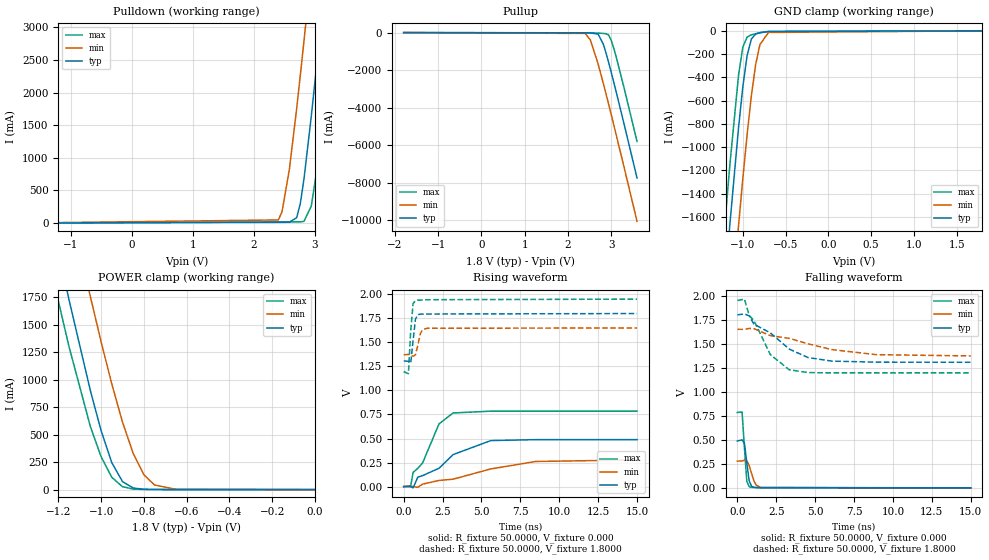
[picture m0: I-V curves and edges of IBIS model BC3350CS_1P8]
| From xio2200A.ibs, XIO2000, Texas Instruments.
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|   Model BC3350CS_1P8
[Model]   BC3350CS_1P8
Model_type   I/O
Polarity   Non-Inverting
Enable   Active-Low
Vinl =   0.54V
Vinh =   1.26V
Vmeas =   0.9V
Cref =   15.0pF
Rref =   100M
Vref =   0.00V
|   typ   min   max
C_comp   1.63pF   1.63pF   1.64pF
[Model Spec]
|   typ   min   max
Vinh   1.260V   1.155V   1.365V
Vinl   0.540V   0.495V   0.585V
Vmeas   0.900V   0.825V   0.975V
[Temperature Range]   25.0   125.0   -40.0
[Voltage Range]   1.80V   1.65V   1.95V
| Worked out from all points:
|   slope of the pulldown table from 0 to 0.27 V, typ, clamps not added: 51.9 ohm
|   slope of the pullup table from 0 to 0.27 V, typ, clamps not added: 72 ohm
|   GND clamp passes 1 mA (typ) near -0.59 V on its own axis
|   POWER clamp passes 1 mA (typ) near -0.75 V on its own axis
|   rising waveform, R_fixture 50.0000, V_fixture 0.000: 20-80 % time 2.74ns typ, 5.16ns min, 1.54ns max; typ from 0 V to 0.488 V
|   rising waveform, R_fixture 50.0000, V_fixture 1.8000: 20-80 % time 199ps typ, 241ps min, 188ps max; typ from 1.31 V to 1.8 V
|   falling waveform, R_fixture 50.0000, V_fixture 0.000: 20-80 % time 230ps typ, 348ps min, 199ps max; typ from 0.488 V to 0 V
|   falling waveform, R_fixture 50.0000, V_fixture 1.8000: 20-80 % time 2.65ns typ, 4.66ns min, 1.55ns max; typ from 1.8 V to 1.31 V
| (Vdd votage range)   1.50V   1.35V   1.65V
| (Process strength)   nominal   weak   strong
[Pulldown]
| voltage   I(typ)   I(min)   I(max)
-1.8V     -654.2uA   -468.5uA   -753.5uA
2.4V      10.51mA    46.93mA    15.78mA
2.46V     10.7mA     169.4mA    15.83mA
2.58V     12.15mA    818.2mA    16.11mA
2.7V      81.06mA    1.755A     16.82mA
2.76V     300.4mA    2.267A     17.73mA
2.82V     678.1mA    2.795A     25.01mA
2.94V     1.642A     3.882A     262.8mA
3.06V     2.709A     4.995A     991.1mA
3.12V     3.26A      5.558A     1.466A
3.3V      4.95A      7.266A     3.059A
3.6V      7.83A      10.15A     5.897A
[Pullup]
| voltage   I(typ)   I(min)   I(max)
-1.8V     538uA      376.5uA    737.9uA
2.4V      -11.82mA   -45.61mA   -17.67mA
2.52V     -17.7mA    -390.5mA   -18.1mA
2.7V      -80.03mA   -1.677A    -28.29mA
2.82V     -618.6mA   -2.71A     -45.98mA
2.88V     -1.07A     -3.247A    -60.47mA
2.94V     -1.568A    -3.794A    -125.5mA
3V        -2.092A    -4.347A    -388.2mA
3.06V     -2.632A    -4.905A    -816.6mA
3.12V     -3.182A    -5.468A    -1.314A
3.3V      -4.872A    -7.174A    -2.945A
3.6V      -7.751A    -10.06A    -5.806A
[GND_clamp]
| voltage   I(typ)   I(min)   I(max)
-1.8V     -7.751A    -8.611A    -7.26A
-1.25V    -2.54A     -3.428A    -2.021A
-1.2V     -2.091A    -2.977A    -1.573A
-1.15V    -1.653A    -2.533A    -1.141A
-1.05V    -833.6mA   -1.675A    -381.3mA
-1V       -481.8mA   -1.271A    -140.2mA
-950mV    -212.8mA   -893.9mA   -53.78mA
-900mV    -70.89mA   -558.6mA   -34.35mA
-850mV    -27.49mA   -290.5mA   -24.87mA
-800mV    -15.42mA   -118.3mA   -17.13mA
-700mV    -5.579mA   -14.05mA   -5.6mA
1.8V      108.1pA    25.63nA    93.5pA
[POWER_clamp]
| voltage   I(typ)   I(min)   I(max)
-1.8V     7.829A     8.704A     7.346A
-1.2V     2.167A     3.062A     1.716A
-1.15V    1.727A     2.616A     1.3A
-1.05V    899.2mA    1.754A     572.6mA
-1V       536.3mA    1.345A     298.8mA
-950mV    245.3mA    960.6mA    111.5mA
-900mV    72.81mA    614.2mA    26.23mA
-850mV    14.59mA    328.9mA    4.932mA
-800mV    2.989mA    135.1mA    1.575mA
-750mV    997.4uA    41.7mA     924.5uA
-650mV    310.2uA    2.816mA    338.3uA
0V        108.1pA    1.97nA     104.9pA
[Ramp]
| variable   typ   min   max
dV/dt_r   0.2928/2.7176n   0.1664/5.1109n   0.4706/1.5201n
dV/dt_f   0.2955/2.6271n   0.1664/4.6144n   0.4527/1.5357n
R_load = 50.0000
[Rising Waveform]
R_fixture = 50.0000
V_fixture = 0.000
V_fixture_min = 0.000
V_fixture_max = 0.000
| time   V(typ)   V(min)   V(max)
0s        803pV      24.91nV    435.3pV
454.5ps   -1.401mV   777.2uV    8.095mV
606.1ps   -13.53mV   535.4uV    147mV
909.1ps   98.07mV    -8.632mV   190.1mV
1.212ns   113.5mV    25.39mV    244.5mV
2.273ns   190.5mV    63.7mV     652.3mV
3.182ns   332.9mV    76.68mV    765.8mV
5.606ns   478.6mV    183.8mV    784.4mV
8.485ns   487.9mV    260.8mV    784.4mV
15ns      488.1mV    277.4mV    784.4mV
[Rising Waveform]
R_fixture = 50.0000
V_fixture = 1.8000
V_fixture_min = 1.6500
V_fixture_max = 1.9500
| time   V(typ)   V(min)   V(max)
0s        1.307V     1.372V     1.196V
303ps     1.303V     1.374V     1.174V
454.5ps   1.288V     1.367V     1.627V
606.1ps   1.523V     1.355V     1.903V
757.6ps   1.743V     1.371V     1.936V
909.1ps   1.787V     1.468V     1.94V
1.061ns   1.794V     1.586V     1.94V
1.212ns   1.795V     1.632V     1.942V
1.515ns   1.795V     1.647V     1.944V
15ns      1.8V       1.65V      1.95V
[Falling Waveform]
R_fixture = 50.0000
V_fixture = 0.000
V_fixture_min = 0.000
V_fixture_max = 0.000
| time   V(typ)   V(min)   V(max)
0s        488.1mV    277.6mV    784.4mV
303ps     499.3mV    280.5mV    789.8mV
454.5ps   463.6mV    287.6mV    413.6mV
606.1ps   260.4mV    281mV      70.01mV
757.6ps   74.37mV    231.8mV    12.37mV
909.1ps   16.58mV    151.7mV    5.214mV
1.061ns   5.188mV    75.42mV    3.972mV
1.212ns   3.034mV    27.51mV    3.312mV
1.515ns   2.017mV    3.965mV    1.862mV
15ns      21.31nV    2.775uV    242.2nV
[Falling Waveform]
R_fixture = 50.0000
V_fixture = 1.8000
V_fixture_min = 1.6500
V_fixture_max = 1.9500
| time   V(typ)   V(min)   V(max)
0s        1.8V       1.65V      1.95V
454.5ps   1.81V      1.65V      1.964V
757.6ps   1.79V      1.659V     1.795V
1.061ns   1.704V     1.657V     1.742V
2.121ns   1.613V     1.584V     1.386V
3.333ns   1.444V     1.556V     1.229V
4.546ns   1.356V     1.499V     1.2V
6.061ns   1.319V     1.439V     1.196V
8.939ns   1.308V     1.386V     1.196V
15ns      1.307V     1.373V     1.196V
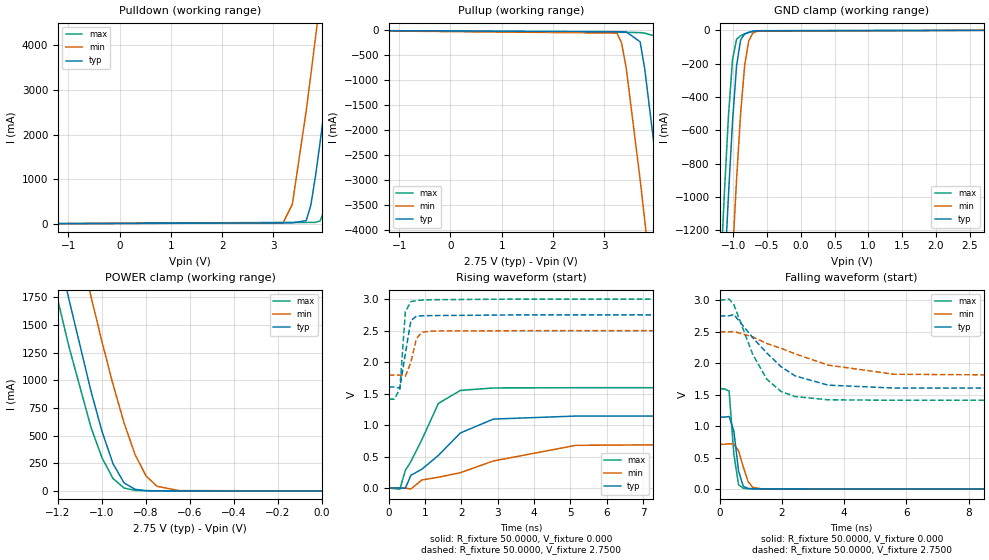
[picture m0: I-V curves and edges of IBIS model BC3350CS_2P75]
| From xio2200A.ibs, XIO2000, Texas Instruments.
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|   Model BC3350CS_2P75
[Model]   BC3350CS_2P75
Model_type   I/O
Polarity   Non-Inverting
Enable   Active-Low
Vinl =   0.8200V
Vinh =   1.9300V
Vmeas =   1.3800V
Cref =   15.0pF
Rref =   100M
Vref =   0.00V
|   typ   min   max
C_comp   1.71pF   1.77pF   1.69pF
[Model Spec]
|   typ   min   max
Vinh   1.93V   1.75V   2.10V
Vinl   0.82V   0.75V   0.90V
Vmeas   1.38V   1.25V   1.50V
[Temperature Range]   25.0   125.0   -40.0
[Voltage Range]   2.75V   2.50V   3.00V
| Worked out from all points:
|   slope of the pulldown table from 0 to 0.412 V, typ, clamps not added: 34.6 ohm
|   slope of the pullup table from 0 to 0.412 V, typ, clamps not added: 48.8 ohm
|   GND clamp passes 1 mA (typ) near -0.59 V on its own axis
|   POWER clamp passes 1 mA (typ) near -0.75 V on its own axis
|   rising waveform, R_fixture 50.0000, V_fixture 0.000: 20-80 % time 1.4ns typ, 2.73ns min, 800ps max; typ from 0 V to 1.14 V
|   rising waveform, R_fixture 50.0000, V_fixture 2.7500: 20-80 % time 195ps typ, 189ps min, 118ps max; typ from 1.6 V to 2.75 V
|   falling waveform, R_fixture 50.0000, V_fixture 0.000: 20-80 % time 187ps typ, 269ps min, 183ps max; typ from 1.14 V to 0 V
|   falling waveform, R_fixture 50.0000, V_fixture 2.7500: 20-80 % time 1.47ns typ, 2.53ns min, 934ps max; typ from 2.75 V to 1.6 V
| (Vdd votage range)   1.50V   1.35V   1.65V
| (Process strength)   nominal   weak   strong
[Pulldown]
| voltage   I(typ)   I(min)   I(max)
-2.75V    -428uA     -334uA     -470uA
3.19V     23.93mA    22.8mA     33.02mA
3.37V     24.22mA    440.4mA    33.12mA
3.64V     74.24mA    2.53A      33.58mA
3.73V     418.4mA    3.335A     34.11mA
3.82V     1.061A     4.159A     35.52mA
3.91V     1.817A     4.995A     66.01mA
4V        2.619A     5.842A     316.8mA
4.18V     4.289A     7.553A     1.552A
4.45V     6.865A     10.15A     3.993A
4.54V     7.733A     11.02A     4.845A
5.44V     16.53A     19.82A     13.61A
[Pullup]
| voltage   I(typ)   I(min)   I(max)
-2.69V    349uA      272uA      421uA
3.25V     -26.63mA   -54.43mA   -39.52mA
3.34V     -27.5mA    -257mA     -39.61mA
3.43V     -30.87mA   -758.6mA   -39.71mA
3.7V      -228.6mA   -2.978A    -45.23mA
3.79V     -765.9mA   -3.794A    -55.21mA
3.97V     -2.272A    -5.468A    -108.9mA
4.06V     -3.091A    -6.318A    -459.5mA
4.15V     -3.929A    -7.174A    -1.147A
4.42V     -6.497A    -9.768A    -3.604A
4.51V     -7.365A    -10.64A    -4.46A
5.5V      -17.05A    -20.32A    -14.13A
[GND_clamp]
| voltage   I(typ)   I(min)   I(max)
-2.75V    -17.05A    -17.86A    -16.59A
-1.19V    -2.002A    -2.887A    -1.485A
-1.13V    -1.481A    -2.357A    -974mA
-1.07V    -988.2mA   -1.843A    -513.5mA
-1.01V    -547.1mA   -1.35A     -175.6mA
-950mV    -212.8mA   -893.9mA   -53.78mA
-890mV    -56.89mA   -498.7mA   -32.19mA
-830mV    -21.15mA   -209mA     -21.63mA
-770mV    -11.63mA   -62.48mA   -13.06mA
-710mV    -6.281mA   -17.15mA   -6.465mA
-650mV    -2.795mA   -5.685mA   -2.37mA
2.71V     161.2pA    121.2nA    140.1pA
[POWER_clamp]
| voltage   I(typ)   I(min)   I(max)
-2.75V    17.12A     17.96A     16.66A
-1.2V     2.167A     3.062A     1.716A
-1.15V    1.727A     2.616A     1.3A
-1.05V    899.2mA    1.754A     572.6mA
-1V       536.3mA    1.345A     298.8mA
-950mV    245.3mA    960.6mA    111.5mA
-900mV    72.81mA    614.2mA    26.23mA
-850mV    14.59mA    328.9mA    4.932mA
-800mV    2.989mA    135.1mA    1.575mA
-750mV    997.4uA    41.7mA     924.5uA
-650mV    310.2uA    2.816mA    338.3uA
0V        166.9pA    2.584nA    161.6pA
[Ramp]
| variable   typ   min   max
dV/dt_r   0.6862/1.3889n   0.4277/2.7000n   0.9559/0.7918n
dV/dt_f   0.6878/1.4530n   0.4241/2.5089n   0.9530/0.9244n
R_load = 50.0000
[Rising Waveform]
R_fixture = 50.0000
V_fixture = 0.000
V_fixture_min = 0.000
V_fixture_max = 0.000
| time   V(typ)   V(min)   V(max)
0s        1.165nV    30.15nV    566.8pV
303ps     245.9uV    982.9uV    -17.68mV
454.5ps   -3.561mV   -1.183mV   282.1mV
606.1ps   202.5mV    -15.34mV   419.4mV
909.1ps   299.3mV    128mV      767.5mV
1.364ns   518.6mV    171.9mV    1.343V
1.97ns    874.7mV    243.5mV    1.55V
2.879ns   1.095V     429.9mV    1.589V
5.152ns   1.143V     678.4mV    1.593V
15ns      1.144V     712.9mV    1.593V
[Rising Waveform]
R_fixture = 50.0000
V_fixture = 2.7500
V_fixture_min = 2.5000
V_fixture_max = 3.0000
| time   V(typ)   V(min)   V(max)
0s        1.604V     1.793V     1.412V
151.5ps   1.604V     1.793V     1.412V
303ps     1.585V     1.793V     1.571V
454.5ps   2.136V     1.776V     2.798V
606.1ps   2.66V      1.995V     2.959V
757.6ps   2.728V     2.37V      2.976V
909.1ps   2.734V     2.473V     2.983V
1.212ns   2.738V     2.493V     2.99V
3.636ns   2.749V     2.498V     3V
15ns      2.75V      2.5V       3V
[Falling Waveform]
R_fixture = 50.0000
V_fixture = 0.000
V_fixture_min = 0.000
V_fixture_max = 0.000
| time   V(typ)   V(min)   V(max)
0s        1.144V     712.9mV    1.593V
151.5ps   1.144V     712.9mV    1.593V
303ps     1.154V     720.5mV    1.558V
454.5ps   922.5mV    716.6mV    558.9mV
606.1ps   289.3mV    608.7mV    71mV
757.6ps   44.97mV    353.9mV    14.61mV
909.1ps   11.72mV    125.2mV    7.665mV
1.061ns   7.02mV     28.39mV    5.42mV
1.364ns   4.248mV    3.668mV    2.958mV
15ns      375.4nV    195.7nV    251.4nV
[Falling Waveform]
R_fixture = 50.0000
V_fixture = 2.7500
V_fixture_min = 2.5000
V_fixture_max = 3.0000
| time   V(typ)   V(min)   V(max)
0s        2.75V      2.5V       3V
303ps     2.753V     2.498V     3.019V
454.5ps   2.775V     2.504V     2.931V
1.061ns   2.407V     2.418V     2.142V
1.515ns   2.162V     2.313V     1.746V
1.97ns    1.946V     2.238V     1.552V
2.424ns   1.799V     2.149V     1.471V
3.485ns   1.652V     1.97V      1.419V
5.606ns   1.606V     1.825V     1.412V
15ns      1.604V     1.793V     1.412V
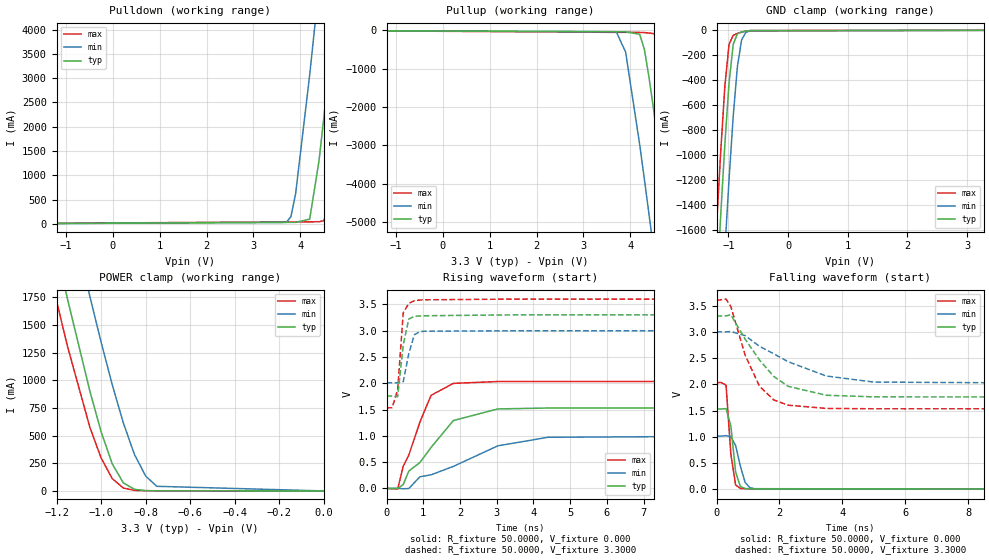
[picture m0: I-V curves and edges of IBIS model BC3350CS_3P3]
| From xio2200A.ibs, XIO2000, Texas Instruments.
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|   Model BC3350CS_3P3
[Model]   BC3350CS_3P3
Model_type   I/O
Enable   Active-Low
Polarity   Non-Inverting
Vinl =   0.99000V
Vinh =   2.31000V
Vmeas =   1.65000V
Cref =  15.00000pF
Rref = 100.00000M
Vref = 0.0000V
|   typ   min   max
C_comp   2.11pf   2.20pf   2.12pf
[Model Spec]
|   typ   min   max
Vinh   2.31V   2.10V   2.52V
Vinl   0.99V   0.90V   1.08V
Vmeas   1.65V   1.50V   1.80V
[Temperature Range]   25.0   125.0   -40.0
[Voltage Range]   3.30V   3.00V   3.60V
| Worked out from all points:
|   slope of the pulldown table from 0 to 0.495 V, typ, clamps not added: 30.8 ohm
|   slope of the pullup table from 0 to 0.495 V, typ, clamps not added: 43 ohm
|   GND clamp passes 1 mA (typ) near -0.59 V on its own axis
|   POWER clamp passes 1 mA (typ) near -0.75 V on its own axis
|   rising waveform, R_fixture 50.0000, V_fixture 0.000: 20-80 % time 1.12ns typ, 2.16ns min, 658ps max; typ from 0 V to 1.53 V
|   rising waveform, R_fixture 50.0000, V_fixture 3.3000: 20-80 % time 182ps typ, 202ps min, 128ps max; typ from 1.76 V to 3.3 V
|   falling waveform, R_fixture 50.0000, V_fixture 0.000: 20-80 % time 172ps typ, 258ps min, 178ps max; typ from 1.53 V to 0 V
|   falling waveform, R_fixture 50.0000, V_fixture 3.3000: 20-80 % time 1.22ns typ, 2.03ns min, 808ps max; typ from 3.3 V to 1.76 V
| (Vdd votage range)   1.50V   1.35V   1.65V
| (Process strength)   nominal   weak   strong
[Pulldown]
| voltage   I(typ)   I(min)   I(max)
-3.3V     -368uA     -295uA     -396uA
3.7V      32.25mA    31.14mA    43.09mA
3.8V      32.33mA    150.2mA    43.16mA
3.9V      32.52mA    621.8mA    43.24mA
4.2V      98.73mA    3.065A     43.69mA
4.4V      1.307A     4.902A     45.29mA
4.5V      2.17A      5.842A     66.67mA
4.6V      3.077A     6.79A      322.6mA
4.8V      4.951A     8.705A     1.723A
4.9V      5.905A     9.668A     2.605A
5.2V      8.8A       12.58A     5.419A
6.6V      22.55A     26.32A     19.14A
[Pullup]
| voltage   I(typ)   I(min)   I(max)
-3.3V     286uA      231uA      330uA
3.7V      -37mA      -36.04mA   -52.76mA
3.9V      -38.31mA   -567.5mA   -52.99mA
4.2V      -102.7mA   -2.979A    -53.99mA
4.3V      -495.7mA   -3.887A    -58.56mA
4.4V      -1.237A    -4.813A    -69.85mA
4.5V      -2.095A    -5.751A    -86.73mA
4.6V      -3A        -6.698A    -177.8mA
4.8V      -4.873A    -8.612A    -1.579A
5.1V      -7.752A    -11.51A    -4.365A
5.2V      -8.722A    -12.48A    -5.324A
6.6V      -22.48A    -26.23A    -19.07A
[GND_clamp]
| voltage   I(typ)   I(min)   I(max)
-3.3V     -22.48A    -23.27A    -22.04A
-1.2V     -2.091A    -2.977A    -1.573A
-1.13V    -1.481A    -2.357A    -974mA
-1.06V    -910.1mA   -1.759A    -445.6mA
-990mV    -419.8mA   -1.193A    -111.9mA
-920mV    -111.8mA   -686.4mA   -39.65mA
-850mV    -27.49mA   -290.5mA   -24.87mA
-780mV    -12.77mA   -77.68mA   -14.36mA
-710mV    -6.281mA   -17.15mA   -6.465mA
-640mV    -2.381mA   -4.808mA   -1.936mA
3.28V     199.9pA    703.3nA    170pA
[POWER_clamp]
| voltage   I(typ)   I(min)   I(max)
-3.3V     22.55A     23.36A     22.1A
-1.25V    2.617A     3.515A     2.152A
-1.2V     2.167A     3.062A     1.716A
-1.15V    1.727A     2.616A     1.3A
-1.05V    899.2mA    1.754A     572.6mA
-1V       536.3mA    1.345A     298.8mA
-950mV    245.3mA    960.6mA    111.5mA
-900mV    72.81mA    614.2mA    26.23mA
-850mV    14.59mA    328.9mA    4.932mA
-800mV    2.989mA    135.1mA    1.575mA
-750mV    997.4uA    41.7mA     924.5uA
0V        203.4pA    3.019nA    194.4pA
[Ramp]
| variable   typ   min   max
dV/dt_r   0.9174/1.1080n   0.6072/2.1416n   1.2196/0.6514n
dV/dt_f   0.9259/1.2121n   0.5953/2.0141n   1.2405/0.7996n
R_load = 50.0000
[Rising Waveform]
R_fixture = 50.0000
V_fixture = 0.000
V_fixture_min = 0.000
V_fixture_max = 0.000
| time   V(typ)   V(min)   V(max)
0s        1.49nV     34.72nV    671.9pV
303ps     -3.357mV   1.385mV    -14.66mV
454.5ps   73.69mV    -7.318mV   421.4mV
606.1ps   329.8mV    -2.808mV   634.3mV
909.1ps   492mV      221.1mV    1.262V
1.212ns   778.4mV    258.3mV    1.769V
1.818ns   1.29V      418mV      1.997V
3.03ns    1.511V     809.2mV    2.032V
4.394ns   1.528V     971.8mV    2.033V
15ns      1.529V     1.012V     2.033V
[Rising Waveform]
R_fixture = 50.0000
V_fixture = 3.3000
V_fixture_min = 3.0000
V_fixture_max = 3.6000
| time   V(typ)   V(min)   V(max)
0s        1.757V     2.008V     1.533V
151.5ps   1.757V     2.008V     1.533V
303ps     1.743V     2.006V     1.872V
454.5ps   2.733V     2.026V     3.338V
606.1ps   3.22V      2.563V     3.518V
757.6ps   3.272V     2.921V     3.57V
909.1ps   3.279V     2.981V     3.581V
1.061ns   3.283V     2.989V     3.586V
3.485ns   3.3V       2.997V     3.6V
15ns      3.3V       3V         3.6V
[Falling Waveform]
R_fixture = 50.0000
V_fixture = 0.000
V_fixture_min = 0.000
V_fixture_max = 0.000
| time   V(typ)   V(min)   V(max)
0s        1.529V     1.012V     2.033V
151.5ps   1.529V     1.012V     2.033V
303ps     1.536V     1.02V      1.984V
454.5ps   1.207V     1.004V     670.5mV
606.1ps   329.7mV    831.6mV    79.49mV
757.6ps   47.92mV    437.4mV    13.47mV
909.1ps   12.78mV    128.5mV    8.217mV
1.061ns   7.667mV    26.97mV    6.068mV
1.212ns   6.065mV    8.864mV    4.526mV
15ns      359.4nV    457.2nV    237.2nV
[Falling Waveform]
R_fixture = 50.0000
V_fixture = 3.3000
V_fixture_min = 3.0000
V_fixture_max = 3.6000
| time   V(typ)   V(min)   V(max)
0s        3.3V       3V         3.6V
303ps     3.305V     2.999V     3.625V
454.5ps   3.325V     3.006V     3.483V
909.1ps   2.86V      2.928V     2.555V
1.364ns   2.463V     2.725V     1.964V
1.818ns   2.15V      2.581V     1.702V
2.273ns   1.961V     2.431V     1.601V
3.485ns   1.791V     2.158V     1.54V
5ns       1.76V      2.042V     1.533V
15ns      1.757V     2.008V     1.533V
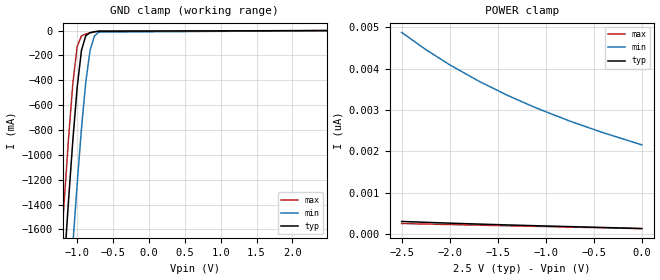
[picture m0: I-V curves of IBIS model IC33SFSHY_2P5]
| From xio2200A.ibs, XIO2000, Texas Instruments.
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|************************ IC33SFSHY @ 2.5V************************
[Model]   IC33SFSHY_2P5
Model_type   Input
Polarity   Non-Inverting
Vinh = 1.75V
Vinl = 0.75V
|   typ   min   max
C_comp   1.563pF   1.592pF   1.553pF
[Model Spec]
|   typ   min   max
Vinh   1.750V   1.575V   1.925V
Vinl   0.750V   0.675V   0.825V
[Temperature Range]   25   125   -40
[Voltage Range]   2.50V   2.25V   2.75V
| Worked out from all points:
|   GND clamp passes 1 mA (typ) near -0.59 V on its own axis
| (Vdd votage range)   1.50V   1.35V   1.65V
[GND_clamp]
| voltage   I(typ)   I(min)   I(max)
-2.5V     -14.56A    -15.37A    -14.1A
-1.24V    -2.42A     -3.298A    -1.907A
-1.18V    -1.885A    -2.759A    -1.375A
-1.12V    -1.369A    -2.232A    -871mA
-1.06V    -884.2mA   -1.722A    -426.9mA
-1V       -460.1mA   -1.237A    -129mA
-940mV    -160.3mA   -792mA     -42.89mA
-880mV    -41.5mA    -417.1mA   -27.16mA
-820mV    -16.93mA   -160.2mA   -18.08mA
-760mV    -9.494mA   -44.89mA   -10.64mA
-700mV    -5.012mA   -12.52mA   -5.062mA
2.48V     130.4pA    2.323nA    114.2pA
[POWER_clamp]
| voltage   I(typ)   I(min)   I(max)
-2.5V     303.5pA    4.879nA    253.7pA
-2.25V    282.2pA    4.465nA    240.9pA
-2V       262.3pA    4.095nA    228.4pA
-1.7V     240.2pA    3.703nA    213.7pA
-1.4V     219.4pA    3.357nA    198.9pA
-1.1V     199.8pA    3.051nA    184.4pA
-750mV    178pA      2.733nA    167.3pA
-400mV    157.1pA    2.45nA     150.6pA
0V        132.2pA    2.158nA    129pA
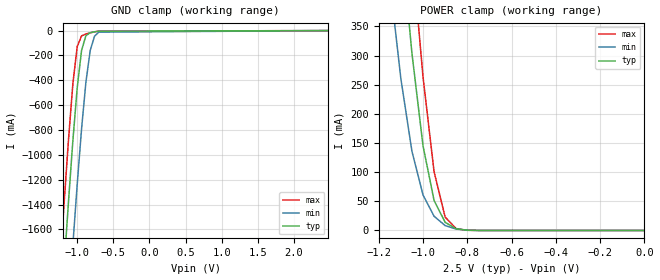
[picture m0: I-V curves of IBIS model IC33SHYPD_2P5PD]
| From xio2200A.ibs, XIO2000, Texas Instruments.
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|   Model IC33SHYPD_2P5PD
[Model]   IC33SHYPD_2P5PD
Model_type   Input
Polarity   Non-Inverting
Vinh =   1.75V
Vinl =   0.75V
|   typ   min   max
C_comp   1.62pF   1.62pF   1.62pF
[Model Spec]
|   typ   min   max
Vinh   1.750V   1.575V   1.925V
Vinl   0.750V   0.675V   0.825V
[Temperature Range]   25.0000   0.1250k   -40.0000
[Voltage Range]   2.5000V   2.2500V   2.7500V
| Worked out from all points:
|   GND clamp passes 1 mA (typ) near -0.59 V on its own axis
|   POWER clamp passes 1 mA (typ) near -0.81 V on its own axis
| (Vdd votage range)   1.50V   1.35V   1.65V
[GND_clamp]
| voltage   I(typ)   I(min)   I(max)
-2.5V     -14.56A    -15.37A    -14.1A
-1.24V    -2.42A     -3.298A    -1.907A
-1.18V    -1.885A    -2.759A    -1.375A
-1.12V    -1.369A    -2.232A    -871mA
-1.06V    -884.3mA   -1.722A    -427mA
-1V       -460.1mA   -1.237A    -129.1mA
-940mV    -160.3mA   -792.1mA   -42.92mA
-880mV    -41.54mA   -417.2mA   -27.16mA
-820mV    -16.95mA   -160.2mA   -18.08mA
-760mV    -9.5mA     -44.93mA   -10.64mA
-700mV    -5.013mA   -12.54mA   -5.062mA
2.48V     143.1pA    2.391nA    127pA
[POWER_clamp]
| voltage   I(typ)   I(min)   I(max)
-2.5V     8.108A     7.368A     8.703A
-1.15V    732.8mA    427.8mA    979.7mA
-1.1V     506.2mA    260.6mA    722.8mA
-1.05V    304.3mA    136mA      480.1mA
-1V       145.5mA    61.04mA    263.8mA
-950mV    51.56mA    24.44mA    101mA
-900mV    14.01mA    8.383mA    22.94mA
-850mV    2.793mA    2.36mA     3.142mA
-800mV    442.5uA    587.5uA    300.2uA
-750mV    66.2uA     140.7uA    26.86uA
0V        145.1pA    2.172nA    143pA
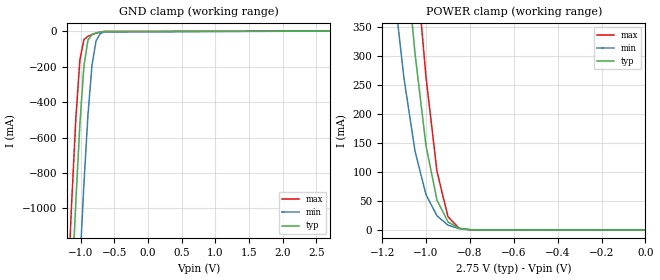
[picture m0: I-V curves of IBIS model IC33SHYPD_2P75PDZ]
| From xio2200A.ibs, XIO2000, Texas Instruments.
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|   Model IC33SHYPD_2P75PDZ
[Model]   IC33SHYPD_2P75PDZ
Model_type   Input
Polarity   Non-Inverting
Vinl =   0.8200V
Vinh =   1.9300V
C_comp   1.6800pF   1.6800pF   1.6800pF
[Model Spec]
|   typ   min   max
Vinh   1.930V   1.750V   2.10V
Vinl   0.820V   0.750V   0.90V
[Temperature Range]   25.0000   0.1250k   -40.0000
[Voltage Range]   2.7500V   2.5000V   3.0000V
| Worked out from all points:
|   GND clamp passes 1 mA (typ) near -0.60 V on its own axis
|   POWER clamp passes 1 mA (typ) near -0.81 V on its own axis
| (Vdd votage range)   1.50V   1.35V   1.65V
| (Process strength)   nominal   weak   strong
[GND_clamp]
| voltage   I(typ)   I(min)   I(max)
-2.75V    -17.02A    -17.82A    -16.57A
-1.19V    -1.973A    -2.848A    -1.462A
-1.13V    -1.453A    -2.319A    -952.1mA
-1.07V    -961.9mA   -1.806A    -494.2mA
-1.01V    -524.5mA   -1.315A    -162.9mA
-950mV    -197.8mA   -862.4mA   -48.44mA
-890mV    -51.23mA   -472.9mA   -28.94mA
-830mV    -18.97mA   -192.8mA   -19.47mA
-770mV    -10.44mA   -56.14mA   -11.77mA
-710mV    -5.643mA   -15.3mA    -5.841mA
-650mV    -2.514mA   -5.085mA   -2.147mA
2.71V     150.7pA    2.537nA    132.4pA
[POWER_clamp]
| voltage   I(typ)   I(min)   I(max)
-2.75V    9.52A      8.729A     10.16A
-1.15V    732.8mA    427.8mA    979.7mA
-1.1V     506.2mA    260.6mA    722.8mA
-1.05V    304.3mA    136mA      480.1mA
-1V       145.5mA    61.04mA    263.8mA
-950mV    51.56mA    24.44mA    101mA
-900mV    14.01mA    8.383mA    22.94mA
-850mV    2.793mA    2.36mA     3.142mA
-800mV    442.5uA    587.5uA    300.2uA
-750mV    66.2uA     140.7uA    26.86uA
0V        154.4pA    2.344nA    149.6pA
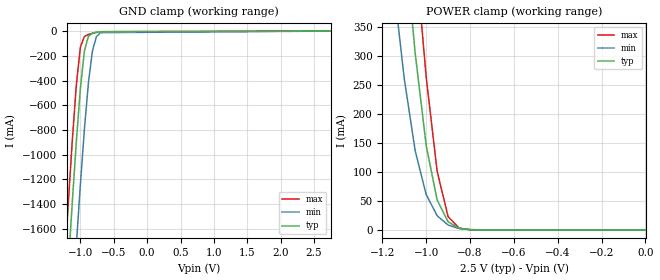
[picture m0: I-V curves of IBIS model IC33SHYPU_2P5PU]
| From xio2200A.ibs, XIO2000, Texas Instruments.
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|   Model IC33SHYPU_2P5PU
[Model]   IC33SHYPU_2P5PU
Model_type   Input
Polarity   Non-Inverting
Vinl =   0.7500V
Vinh =   1.7500V
C_comp   1.6200pF   1.6200pF   1.6200pF
[Temperature Range]   25.0000   0.1250k   -40.0000
[Voltage Range]   2.5000V   2.2500V   2.7500V
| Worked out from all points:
|   GND clamp passes 1 mA (typ) near -0.59 V on its own axis
|   POWER clamp passes 1 mA (typ) near -0.81 V on its own axis
[GND_clamp]
| voltage   I(typ)   I(min)   I(max)
-2.5V     -14.56A    -15.37A    -14.1A
-1.24V    -2.42A     -3.298A    -1.907A
-1.18V    -1.885A    -2.759A    -1.375A
-1.12V    -1.369A    -2.232A    -871mA
-1.06V    -884.3mA   -1.722A    -427mA
-1V       -460.1mA   -1.237A    -129.1mA
-940mV    -160.3mA   -792.1mA   -42.98mA
-880mV    -41.55mA   -417.1mA   -27.25mA
-820mV    -16.99mA   -160.2mA   -18.17mA
-760mV    -9.549mA   -44.92mA   -10.73mA
-700mV    -5.066mA   -12.55mA   -5.153mA
2.75V     0A         12uA       0A
[POWER_clamp]
| voltage   I(typ)   I(min)   I(max)
-2.5V     8.109A     7.368A     8.703A
-1.15V    732.9mA    428mA      979.8mA
-1.1V     506.3mA    260.8mA    722.9mA
-1.05V    304.4mA    136.2mA    480.2mA
-1V       145.7mA    61.22mA    263.9mA
-950mV    51.68mA    24.61mA    101.1mA
-900mV    14.11mA    8.533mA    23.03mA
-850mV    2.873mA    2.487mA    3.227mA
-800mV    503.3uA    691uA      381.1uA
-750mV    117.8uA    221.6uA    102.3uA
2.5mV     0A         500pA      0A
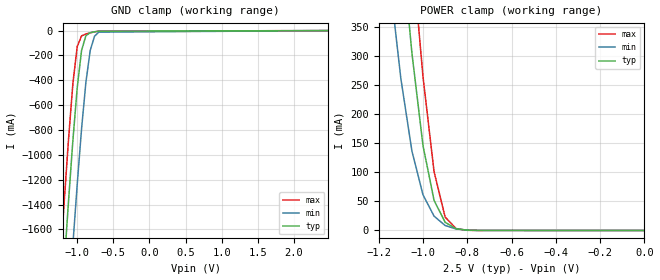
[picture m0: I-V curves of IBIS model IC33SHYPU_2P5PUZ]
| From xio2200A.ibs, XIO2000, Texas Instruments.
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|   Model IC33SHYPU_2P5PUZ
[Model]   IC33SHYPU_2P5PUZ
Model_type   Input
Polarity   Non-Inverting
Vinl =   0.7500V
Vinh =   1.7500V
C_comp   1.6200pF   1.6200pF   1.6200pF
[Temperature Range]   25.0000   0.1250k   -40.0000
[Voltage Range]   2.5000V   2.2500V   2.7500V
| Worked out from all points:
|   GND clamp passes 1 mA (typ) near -0.59 V on its own axis
|   POWER clamp passes 1 mA (typ) near -0.81 V on its own axis
[GND_clamp]
| voltage   I(typ)   I(min)   I(max)
-2.5V     -14.56A    -15.37A    -14.1A
-1.24V    -2.42A     -3.298A    -1.907A
-1.18V    -1.885A    -2.759A    -1.375A
-1.12V    -1.369A    -2.232A    -871mA
-1.06V    -884.2mA   -1.722A    -426.9mA
-1V       -460.1mA   -1.237A    -129mA
-940mV    -160.3mA   -792mA     -42.9mA
-880mV    -41.51mA   -417.1mA   -27.16mA
-820mV    -16.94mA   -160.2mA   -18.08mA
-760mV    -9.496mA   -44.9mA    -10.64mA
-700mV    -5.013mA   -12.52mA   -5.062mA
2.48V     135.3pA    3.355nA    118.5pA
[POWER_clamp]
| voltage   I(typ)   I(min)   I(max)
-2.5V     8.109A     7.368A     8.703A
-1.15V    732.9mA    428mA      979.8mA
-1.1V     506.3mA    260.8mA    722.9mA
-1.05V    304.4mA    136.2mA    480.2mA
-1V       145.7mA    61.22mA    263.9mA
-950mV    51.67mA    24.6mA     101mA
-900mV    14.1mA     8.53mA     22.97mA
-850mV    2.852mA    2.482mA    3.15mA
-800mV    471.9uA    685.6uA    302.8uA
-750mV    76.25uA    214.8uA    28.26uA
0V        137.4pA    2.164nA    134.5pA
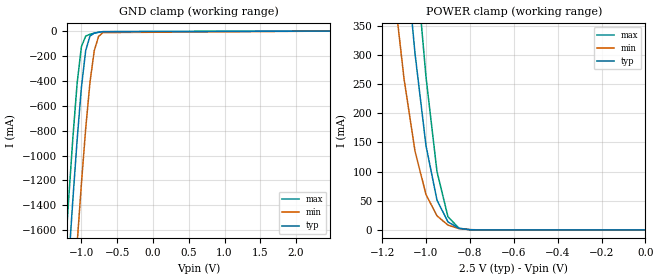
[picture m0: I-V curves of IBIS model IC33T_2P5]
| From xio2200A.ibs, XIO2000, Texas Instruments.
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|************************ IC33T @ 2.5V************************
[Model]   IC33T_2P5
Model_type   Input
Polarity   Non-Inverting
Vinh = 1.75V
Vinl = 0.75V
|   typ   min   max
C_comp   1.521pF   1.546pF   1.512pF
[Model Spec]
|   typ   min   max
Vinh   1.750V   1.575V   1.925V
Vinl   0.750V   0.675V   0.825V
[Temperature Range]   25   125   -40
[Voltage Range]   2.50V   2.25V   2.75V
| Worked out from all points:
|   GND clamp passes 1 mA (typ) near -0.60 V on its own axis
|   POWER clamp passes 1 mA (typ) near -0.81 V on its own axis
| (Vdd votage range)   1.50V   1.35V   1.65V
[GND_clamp]
| voltage   I(typ)   I(min)   I(max)
-2.5V     -14.55A    -15.36A    -14.09A
-1.24V    -2.413A    -3.288A    -1.901A
-1.18V    -1.878A    -2.75A     -1.369A
-1.12V    -1.362A    -2.223A    -865.6mA
-1.06V    -878mA     -1.714A    -422mA
-1V       -454.6mA   -1.229A    -125.4mA
-940mV    -156.6mA   -784.7mA   -40.63mA
-880mV    -39.8mA    -411.2mA   -25.57mA
-820mV    -16.01mA   -156.6mA   -17.01mA
-760mV    -8.939mA   -43.44mA   -10mA
-700mV    -4.714mA   -11.98mA   -4.751mA
2.48V     84.75pA    2.199nA    69.15pA
[POWER_clamp]
| voltage   I(typ)   I(min)   I(max)
-2.5V     8.064A     7.326A     8.657A
-1.15V    728.1mA    424.8mA    974mA
-1.1V     502.9mA    258.7mA    718.5mA
-1.05V    302.1mA    134.9mA    477.1mA
-1V       144.4mA    60.62mA    262mA
-950mV    51.17mA    24.3mA     100.2mA
-900mV    13.92mA    8.343mA    22.77mA
-850mV    2.778mA    2.349mA    3.121mA
-800mV    440uA      584.7uA    298.1uA
-750mV    65.79uA    140uA      26.65uA
0V        86.19pA    1.994nA    79.48pA
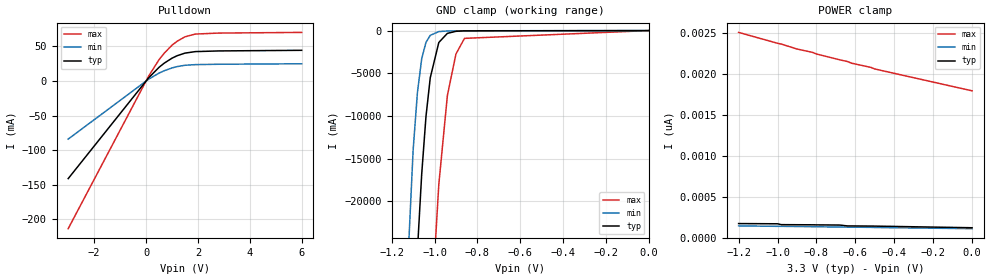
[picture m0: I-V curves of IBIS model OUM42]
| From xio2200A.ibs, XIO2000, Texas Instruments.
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|Extracted from xx21 IBIS model
[Model]   OUM42
Model_type   Open_drain
Enable   Active-Low
Polarity   Non-Inverting
| signals   A, GZ, Y
Vmeas = 1.5
|   typ   min   max
C_comp   1.7939p   1.6976p   1.9426p
|   typ   min   max
[Temperature Range]   25   -40.0   125
|   typ   min   max
[Voltage Range]   3.30V   3.00V   3.60V
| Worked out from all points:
|   slope of the pulldown table from 0 to 0.495 V, typ, clamps not added: 25.4 ohm
|   GND clamp passes 1 mA (typ) near -0.60 V on its own axis
[Pulldown]
|   Voltage   I(typ)   I(min)   I(max)
-3V       -141mA     -83.92mA   -213.3mA
100mV     4.484mA    2.586mA    6.989mA
500mV     19.68mA    11.33mA    30.69mA
700mV     25.7mA     14.77mA    40.14mA
1V        32.89mA    18.8mA     51.56mA
1.2V      36.5mA     20.77mA    57.45mA
1.5V      40.24mA    22.67mA    63.81mA
1.9V      42.43mA    23.63mA    67.78mA
2.8V      43.4mA     24.16mA    69.19mA
6V        44.3mA     24.88mA    70.18mA
[GND_clamp]
|   Voltage   I(typ)   I(min)   I(max)
-1.2V     -108.8A    -79.15A    -162.5A
-1.14V    -62.91A    -35.36A    -114.5A
-1.1V     -36.74A    -14.01A    -84.83A
-1.08V    -25.81A    -7.27A     -70.96A
-1.06V    -16.83A    -3.304A    -57.92A
-1.04V    -10.07A    -1.375A    -45.91A
-1.02V    -5.53A     -560mA     -35.11A
-980mV    -1.393A    -115.7mA   -18.02A
-940mV    -327mA     -47.54mA   -7.615A
-900mV    -86.88mA   -32.48mA   -2.746A
-860mV    -32.18mA   -25.06mA   -911.7mA
0V        0A         0A         0A
[POWER_clamp]
|   Voltage   I(typ)   I(min)   I(max)
-1.2V     175pA      146.6pA    2.511nA
-1V       172.3pA    141.2pA    2.378nA
-980mV    161.7pA    141.2pA    2.368nA
-900mV    160.8pA    139.4pA    2.308nA
-820mV    159.9pA    136.8pA    2.267nA
-800mV    159pA      135.9pA    2.247nA
-680mV    156.8pA    132.3pA    2.176nA
-640mV    146.1pA    131.4pA    2.155nA
-620mV    146.1pA    131.4pA    2.135nA
-520mV    144.3pA    128.8pA    2.083nA
-500mV    143.9pA    127pA      2.064nA
0V        123.9pA    112.8pA    1.797nA
[Ramp]
|   I(typ)   I(min)   I(max)
dV/dt_r   0.001/0.001n   0.001/0.001n   0.001/0.001n
dV/dt_f   1.151/2.350n   0.649/3.545n   1.554/1.305n
| End [Model] OUM42
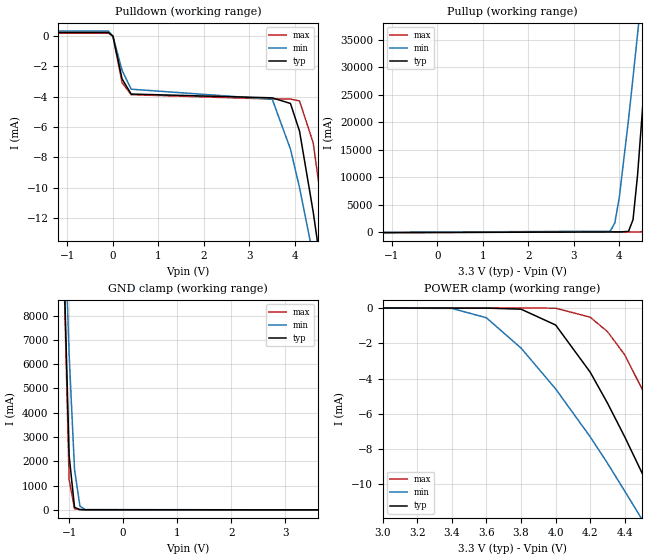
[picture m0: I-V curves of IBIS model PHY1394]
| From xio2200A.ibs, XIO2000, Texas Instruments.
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|   Model PHY1394
[Model]   PHY1394
Model_type   3-state
Polarity   Non-Inverting
| signals   TPAP, TPAN, TPBP, TPBN
Vinl = 1.640V
Vinh = 2.040V
Vmeas = 1.840V
Cref = 10.0pF
Rref = 56
Vref = 1.840
|   typ   min   max
C_comp   1.9p   NA   NA
|   typ   min   max
[Temperature Range]   25   115   0.0
|   typ   min   max
[Voltage Range]   3.30V   3.00V   3.60V
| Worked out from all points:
|   GND clamp passes 1 mA (typ) near -0.61 V on its own axis
[Pulldown]
|Voltage	I(typ)		I(min)		I(max)
-3.6V     230uA      340uA      210uA
-100mV    240uA      340uA      210uA
0V        -177pA     -2.35nA    -614pA
200mV     -2.82mA    -2.25mA    -3.07mA
400mV     -3.82mA    -3.5mA     -3.86mA
3.5V      -4.07mA    -4.16mA    -4.15mA
3.9V      -4.44mA    -7.45mA    -4.15mA
4.1V      -6.27mA    -10mA      -4.28mA
4.4V      -11.6mA    -14.5mA    -7.04mA
4.6V      -15.8mA    -17.9mA    -11.4mA
4.8V      -20.5mA    -21.6mA    -16.6mA
6.6V      -76.8mA    -49.3mA    -80.3mA
[Pullup]
|Voltage	I(typ)		I(min)		I(max)
-3.3V     -141mA     -104mA     -131mA
3.8V      58.1mA     192mA      71.3mA
3.9V      55.5mA     1.7A       67.3mA
4V        55.3mA     6.42A      63.3mA
4.2V      146mA      20.4A      56.7mA
4.3V      2.28A      28.1A      56.7mA
4.4V      10.4A      36A        60.5mA
4.5V      21.4A      44.1A      89.6mA
4.6V      33.4A      52.3A      1.28A
4.7V      45.9A      60.5A      10.2A
4.9V      71.4A      77.1A      39.9A
6.6V      296A       170A       333A
[POWER_clamp]
|Voltage	I(typ)		I(min)		I(max)
3V        -33.2nA    -30.9nA    -36.2nA
3.4V      -34.4nA    -18.2uA    -36.2nA
3.6V      -291nA     -552uA     -36.2nA
3.8V      -62.5uA    -2.27mA    -46.6nA
4V        -962uA     -4.59mA    -8.2uA
4.2V      -3.64mA    -7.31mA    -517uA
4.3V      -5.4mA     -8.81mA    -1.34mA
4.4V      -7.32mA    -10.4mA    -2.66mA
4.5V      -9.37mA    -12mA      -4.6mA
4.6V      -11.5mA    -13.8mA    -6.88mA
4.8V      -16.2mA    -17.4mA    -12mA
6.9V      -72.3mA    -54.1mA    -88.9mA
[GND_clamp]
|Voltage	I(typ)		I(min)		I(max)
-3.6V     296A       170A       438A
-1.1V     10.4A      13A        10.1A
-1V       2.23A      6.39A      1.24A
-900mV    101mA      1.66A      44.1mA
-800mV    11.2mA     148mA      11.6mA
-700mV    3.63mA     11.8mA     4.22mA
3.6V      -33.2nA    -30.9nA    -36.2nA
[Ramp]
|   I(typ)   I(min)   I(max)
dV/dt_r   0.176v/0.637n   0.176v/0.782n   0.176v/0.624n
dV/dt_f   0.176v/0.642n   0.176v/0.742n   0.176v/0.744n
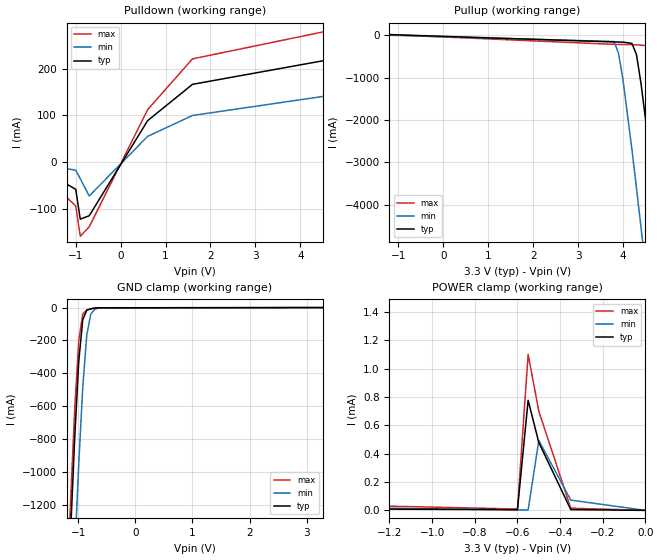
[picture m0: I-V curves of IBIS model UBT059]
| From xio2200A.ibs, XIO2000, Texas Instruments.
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|Extracted from xx21 IBIS Model.
[Model]   UBT059
Model_type   I/O
Polarity   Non-Inverting
Enable   Active-Low
Vinl =   0.9900V
Vinh =   1.6500V
Vmeas =   1.6500V
|   typ   min   max
C_comp   3.7686pF   3.6057pF   3.7926pF
|   typ   min   max
[Temperature Range]   25.0000   0.1150k   0.000
|   typ   min   max
[Voltage Range]   3.3000V   3.0000V   3.6000V
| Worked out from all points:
|   slope of the pulldown table from 0 to 0.495 V, typ, clamps not added: 6.57 ohm
|   slope of the pullup table from 0 to 0.495 V, typ, clamps not added: 16.1 ohm
|   GND clamp passes 1 mA (typ) near -0.62 V on its own axis
|   POWER clamp passes 1 mA (typ) near -2.51 V on its own axis
[Pulldown]
| voltage   I(typ)   I(min)   I(max)
-3.3V     -1.321mA   -839uA     -1.573mA
-2V       -3.161mA   -1.945mA   -3.797mA
-1V       -58.71mA   -17.61mA   -94.37mA
-900mV    -122.7mA   -35.78mA   -159.3mA
-700mV    -115.3mA   -73.03mA   -139.1mA
600mV     88.53mA    54.88mA    112.1mA
1.6V      166.5mA    99.69mA    221.1mA
5.3V      230.8mA    151.7mA    294.7mA
5.5V      240.7mA    198.2mA    307mA
5.6V      245.8mA    360.2mA    313.4mA
6V        353.4mA    2.107A     341.1mA
6.6V      3.202A     5.256A     1.093A
[Pullup]
| voltage   I(typ)   I(min)   I(max)
-3.3V     88.28mA    62.33mA    110.9mA
3.8V      -159mA     -149mA     -216.2mA
3.9V      -160.5mA   -425.6mA   -218.3mA
4V        -163.4mA   -1.05A     -220.1mA
4.2V      -193.9mA   -2.706A    -223.9mA
4.3V      -456.1mA   -3.605A    -227.8mA
4.4V      -1.13A     -4.526A    -234.2mA
4.5V      -1.966A    -5.462A    -246.4mA
4.6V      -2.86A     -6.407A    -378.8mA
4.8V      -4.723A    -8.318A    -1.782A
5.1V      -7.597A    -11.22A    -4.537A
6.6V      -22.32A    -25.93A    -19.19A
[GND_clamp]
| voltage   I(typ)   I(min)   I(max)
-3.3V     -22.31A    -22.97A    -22.15A
-1.2V     -1.946A    -2.694A    -1.753A
-1.13V    -1.343A    -2.082A    -1.154A
-1.06V    -785.7mA   -1.495A    -610.9mA
-990mV    -326mA     -950.3mA   -200.2mA
-920mV    -73.64mA   -484.8mA   -38.8mA
-850mV    -16.3mA    -167.9mA   -14.61mA
-780mV    -6.849mA   -40.1mA    -8.343mA
-710mV    -3.219mA   -9.936mA   -4.38mA
-640mV    -1.218mA   -2.979mA   -1.79mA
3.28V     285.5pA    4.02uA     276.9pA
[POWER_clamp]
| voltage   I(typ)   I(min)   I(max)
-3.3V     3.071A     3.578A     2.481A
-2.7V     144.6mA    603.1mA    5.229mA
-2.55V    2.91mA     123.4mA    337.7uA
-2.45V    148.1uA    20.69mA    236.9uA
-2.35V    45.35uA    1.801mA    155.7uA
-2.3V     30.59uA    446.9uA    120.2uA
-2.2V     14.34uA    37.57uA    63.41uA
-600mV    5.195uA    2.344uA    9.412uA
-550mV    777uA      2.342uA    1.101mA
-500mV    479.4uA    493.2uA    700.1uA
-350mV    5.177uA    72.34uA    15.36uA
0V        299.2pA    1.381nA    358.5pA
[Ramp]
|   I(typ)   I(min)   I(max)
dV/dt_r   1.6089/0.8905n   1.3370/1.7200n   1.8274/0.6869n
dV/dt_f   1.8225/1.0169n   1.5730/1.8874n   2.0222/0.7297n
| End [Model] UBT059
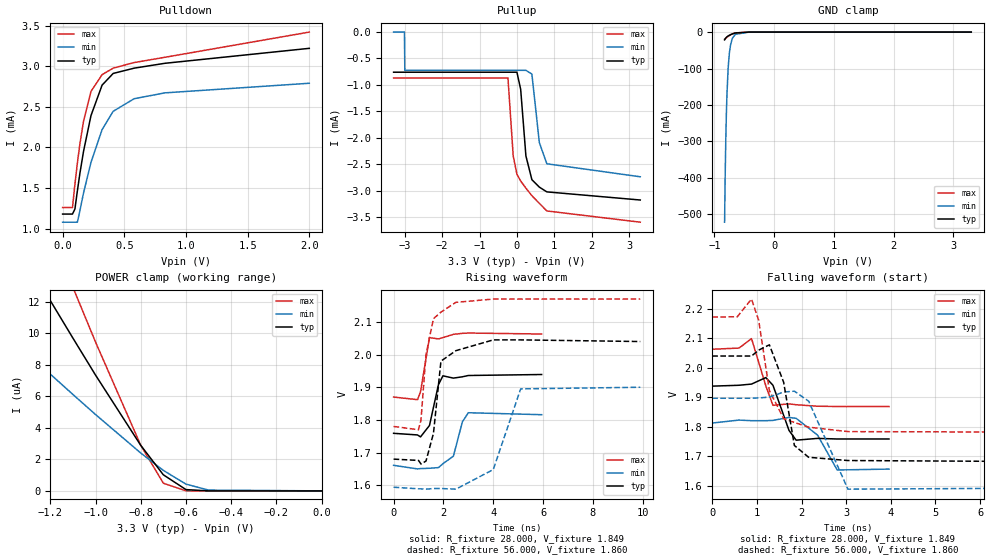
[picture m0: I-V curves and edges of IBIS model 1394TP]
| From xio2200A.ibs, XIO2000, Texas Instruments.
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|   Model PHY1394
[Model] 1394TP
Model_type I/O
Polarity Non-Inverting
Cref = 5.0pF
Rref = 56
Vref = 1.860V
Vmeas =1.860V
Vinl = 0.8
Vinh = 2.0
| typ min max
C_comp 0 NA NA
[Model Spec]
| typ min max
Vmeas 1.860V 1.750V 1.970V
| typ min max
[Temperature Range] 27 125 -40
[Voltage Range] 3.30V 3.00V 3.60V
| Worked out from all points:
|   slope of the pulldown table from 0 to 0.495 V, typ, clamps not added: 280 ohm
|   slope of the pullup table from 0 to 0.495 V, typ, clamps not added: 234 ohm
|   GND clamp passes 1 mA (typ) near -0.60 V on its own axis
|   rising waveform, R_fixture 28.000, V_fixture 1.849: 20-80 % time 267ps typ, 315ps min, 192ps max; typ from 1.76 V to 1.94 V
|   rising waveform, R_fixture 56.000, V_fixture 1.860: 20-80 % time 294ps typ, 633ps min, 315ps max; typ from 1.68 V to 2.04 V
|   falling waveform, R_fixture 28.000, V_fixture 1.849: 20-80 % time 228ps typ, 334ps min, 199ps max; typ from 1.94 V to 1.76 V
|   falling waveform, R_fixture 56.000, V_fixture 1.860: 20-80 % time 247ps typ, 378ps min, 290ps max; typ from 2.04 V to 1.68 V
| (Vdd votage range) 1.50V 1.35V 1.65V
| (Process strength) nominal weak strong
[GND Clamp]
-830mV    -21.31mA   -521.7mA   -19.52mA
-820mV    -18.5mA    -392.5mA   -18.1mA
-810mV    -16.3mA    -295.9mA   -16.74mA
-800mV    -14.51mA   -223.5mA   -15.42mA
-790mV    -13.02mA   -169.2mA   -14.14mA
-770mV    -10.61mA   -98mA      -11.73mA
-750mV    -8.671mA   -57.71mA   -9.515mA
-730mV    -7.03mA    -34.75mA   -7.525mA
-700mV    -4.976mA   -17.09mA   -4.997mA
-650mV    -2.477mA   -6.065mA   -2.103mA
-420mV    -10.61uA   -68.45uA   -2.368uA
3.3V      62.09pA    2.968nA    36.35pA
[Power Clamp]
-3.3V     63.23uA    37.39uA    91.77uA
-1.6V     21.71uA    12.64uA    30.69uA
-1.5V     19.29uA    11.32uA    27.11uA
-1.3V     14.46uA    8.701uA    19.97uA
-1.2V     12.06uA    7.401uA    16.42uA
-1.1V     9.685uA    6.113uA    12.9uA
-1V       7.342uA    4.842uA    9.436uA
-800mV    2.888uA    2.403uA    2.894uA
-700mV    1.022uA    1.302uA    488.5nA
-600mV    84.29nA    432.1nA    6.006nA
-500mV    1.9nA      52.54nA    91.92pA
0V        62.09pA    2.566nA    43.14pA
[Pulldown]
0V        1.18mA     1.08mA     1.26mA
80mV      1.18mA     1.08mA     1.26mA
100mV     1.243mA    1.08mA     1.549mA
120mV     1.468mA    1.08mA     1.81mA
140mV     1.68mA     1.22mA     2.043mA
170mV     1.955mA    1.442mA    2.325mA
230mV     2.392mA    1.816mA    2.69mA
320mV     2.767mA    2.219mA    2.896mA
410mV     2.911mA    2.445mA    2.976mA
580mV     2.976mA    2.6mA      3.045mA
830mV     3.036mA    2.672mA    3.11mA
2V        3.22mA     2.79mA     3.42mA
[Pullup]
-3.3V     -760uA     0A         -868uA
-3.01V    -760uA     0A         -868uA
-3V       -760uA     -724uA     -868uA
-240mV    -760uA     -724uA     -868uA
-100mV    -760uA     -724uA     -2.343mA
0V        -760uA     -724uA     -2.694mA
100mV     -1.083mA   -724uA     -2.82mA
240mV     -2.345mA   -724uA     -2.955mA
400mV     -2.795mA   -795.2uA   -3.098mA
600mV     -2.936mA   -2.094mA   -3.244mA
800mV     -3.026mA   -2.494mA   -3.387mA
3.3V      -3.18mA    -2.74mA    -3.6mA
[Ramp]
| variable   typ   min   max
dV/dt_r 0.216V/0.293919ns  0.1878V/0.622065ns  0.234V/0.315333ns
dV/dt_f 0.2148V/0.246545ns  0.1848V/0.376457ns  0.2298V/0.290951ns
R_load = 56
[Rising Waveform]
R_fixture = 28.000
V_fixture = 1.849
V_fixture_min = 1.739
V_fixture_max = 1.964
|  time   V(typ)   V(min)   V(max)
0s        1.759V     1.661V     1.87V
960ps     1.754V     1.65V      1.862V
1.08ns    1.748V     1.651V     1.886V
1.44ns    1.783V     1.652V     2.052V
1.8ns     1.908V     1.654V     2.048V
1.98ns    1.935V     1.666V     2.052V
2.4ns     1.928V     1.689V     2.062V
2.76ns    1.932V     1.794V     2.065V
3ns       1.936V     1.822V     2.066V
5.94ns    1.939V     1.816V     2.063V
|   6.000nS   1.938V   1.813V   2.063V
[Rising Waveform]
R_fixture = 56.000
V_fixture = 1.860
V_fixture_min = 1.750
V_fixture_max = 1.970
|  time   V(typ)   V(min)   V(max)
0s        1.68V      1.594V     1.78V
1ns       1.676V     1.589V     1.77V
1.1ns     1.665V     1.589V     1.8V
1.3ns     1.674V     1.588V     2V
1.6ns     1.759V     1.59V      2.11V
1.9ns     1.98V      1.59V      2.13V
2.5ns     2.012V     1.588V     2.16V
4ns       2.045V     1.648V     2.17V
5.1ns     2.045V     1.895V     2.17V
9.9ns     2.04V      1.9V       2.17V
|   10.000nS   2.040V   1.897V   2.170V
[Falling Waveform]
R_fixture = 28.000
V_fixture = 1.849
V_fixture_min = 1.739
V_fixture_max = 1.964
|  time   V(typ)   V(min)   V(max)
0s        1.938V     1.813V     2.063V
600ps     1.941V     1.823V     2.067V
880ps     1.945V     1.821V     2.099V
1.2ns     1.967V     1.821V     1.939V
1.36ns    1.941V     1.822V     1.873V
1.72ns    1.788V     1.832V     1.878V
1.88ns    1.755V     1.829V     1.875V
2.36ns    1.761V     1.772V     1.87V
2.8ns     1.759V     1.654V     1.869V
3.96ns    1.759V     1.657V     1.869V
|   4.000nS   1.759V   1.661V   1.869V
[Falling Waveform]
R_fixture = 56.000
V_fixture = 1.860
V_fixture_min = 1.750
V_fixture_max = 1.970
|  time   V(typ)   V(min)   V(max)
0s        2.04V      1.897V     2.172V
560ps     2.04V      1.897V     2.173V
880ps     2.04V      1.897V     2.233V
1.04ns    2.06V      1.898V     2.161V
1.28ns    2.078V     1.901V     1.923V
1.6ns     1.951V     1.918V     1.828V
1.84ns    1.737V     1.921V     1.815V
2.16ns    1.697V     1.887V     1.799V
3.04ns    1.686V     1.589V     1.784V
7.92ns    1.682V     1.593V     1.782V
